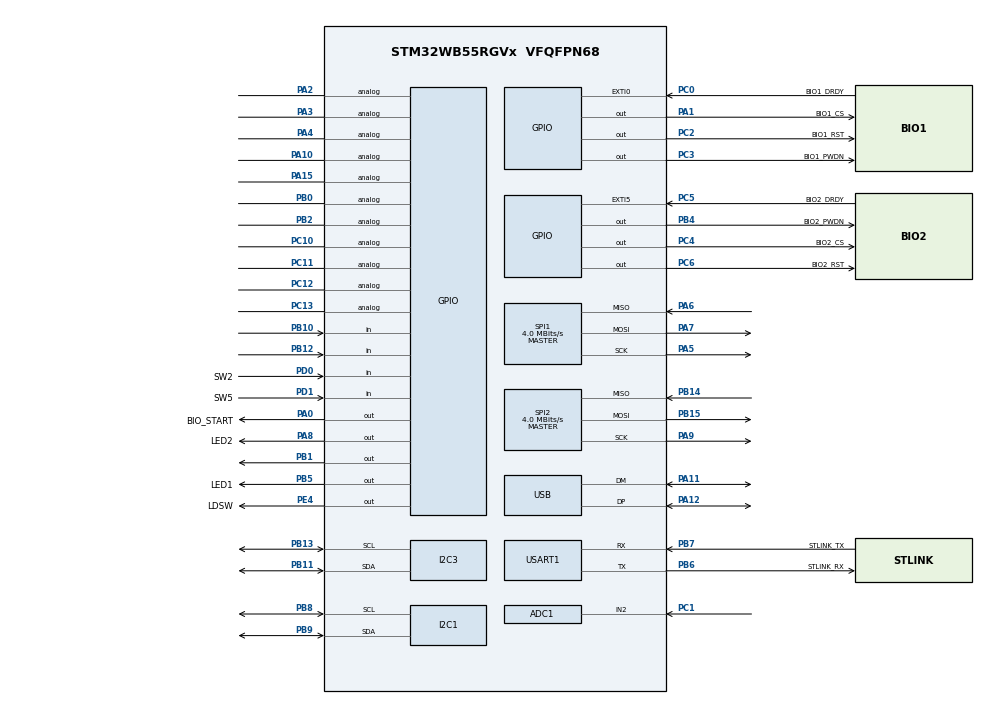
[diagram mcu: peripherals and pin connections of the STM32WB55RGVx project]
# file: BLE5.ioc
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ADC1.Channel-0\#ChannelRegularConversion=ADC_CHANNEL_2
ADC1.NbrOfConversionFlag=1
ADC1.OffsetNumber-0\#ChannelRegularConversion=ADC_OFFSET_NONE
ADC1.Rank-0\#ChannelRegularConversion=1
ADC1.SamplingTime-0\#ChannelRegularConversion=ADC_SAMPLETIME_2CYCLES_5
ADC1.master=1
AES1.KeySize=CRYP_KEYSIZE_256B
Dma.Request0=USART1_TX
Dma.Request1=SPI1_RX
Dma.Request2=SPI1_TX
Dma.SPI1_RX.1.Direction=DMA_PERIPH_TO_MEMORY
Dma.SPI1_RX.1.EventEnable=DISABLE
Dma.SPI1_RX.1.Instance=DMA1_Channel2
Dma.SPI1_RX.1.MemDataAlignment=DMA_MDATAALIGN_BYTE
Dma.SPI1_RX.1.MemInc=DMA_MINC_ENABLE
Dma.SPI1_RX.1.Mode=DMA_NORMAL
Dma.SPI1_RX.1.PeriphDataAlignment=DMA_PDATAALIGN_BYTE
Dma.SPI1_RX.1.PeriphInc=DMA_PINC_DISABLE
Dma.SPI1_RX.1.Polarity=HAL_DMAMUX_REQ_GEN_RISING
Dma.SPI1_RX.1.Priority=DMA_PRIORITY_LOW
Dma.SPI1_RX.1.RequestNumber=1
Dma.SPI1_RX.1.SignalID=NONE
Dma.SPI1_RX.1.SyncEnable=DISABLE
Dma.SPI1_RX.1.SyncPolarity=HAL_DMAMUX_SYNC_NO_EVENT
Dma.SPI1_RX.1.SyncRequestNumber=1
Dma.SPI1_RX.1.SyncSignalID=NONE
Dma.SPI1_TX.2.Direction=DMA_MEMORY_TO_PERIPH
Dma.SPI1_TX.2.EventEnable=DISABLE
Dma.SPI1_TX.2.Instance=DMA1_Channel3
Dma.SPI1_TX.2.MemDataAlignment=DMA_MDATAALIGN_BYTE
Dma.SPI1_TX.2.MemInc=DMA_MINC_ENABLE
Dma.SPI1_TX.2.Mode=DMA_NORMAL
Dma.SPI1_TX.2.PeriphDataAlignment=DMA_PDATAALIGN_BYTE
Dma.SPI1_TX.2.PeriphInc=DMA_PINC_DISABLE
Dma.SPI1_TX.2.Polarity=HAL_DMAMUX_REQ_GEN_RISING
Dma.SPI1_TX.2.Priority=DMA_PRIORITY_LOW
Dma.SPI1_TX.2.RequestNumber=1
Dma.SPI1_TX.2.SignalID=NONE
Dma.SPI1_TX.2.SyncEnable=DISABLE
Dma.SPI1_TX.2.SyncPolarity=HAL_DMAMUX_SYNC_NO_EVENT
Dma.SPI1_TX.2.SyncRequestNumber=1
Dma.SPI1_TX.2.SyncSignalID=NONE
Dma.USART1_TX.0.Direction=DMA_MEMORY_TO_PERIPH
Dma.USART1_TX.0.EventEnable=DISABLE
Dma.USART1_TX.0.Instance=DMA1_Channel1
Dma.USART1_TX.0.MemDataAlignment=DMA_MDATAALIGN_BYTE
Dma.USART1_TX.0.MemInc=DMA_MINC_ENABLE
Dma.USART1_TX.0.Mode=DMA_NORMAL
Dma.USART1_TX.0.PeriphDataAlignment=DMA_PDATAALIGN_BYTE
Dma.USART1_TX.0.PeriphInc=DMA_PINC_DISABLE
Dma.USART1_TX.0.Polarity=HAL_DMAMUX_REQ_GEN_RISING
Dma.USART1_TX.0.Priority=DMA_PRIORITY_LOW
Dma.USART1_TX.0.RequestNumber=1
Dma.USART1_TX.0.SignalID=NONE
Dma.USART1_TX.0.SyncEnable=DISABLE
Dma.USART1_TX.0.SyncPolarity=HAL_DMAMUX_SYNC_NO_EVENT
Dma.USART1_TX.0.SyncRequestNumber=1
Dma.USART1_TX.0.SyncSignalID=NONE
I2C1.Timing=0x10707DBC
I2C3.Timing=0x10707DBC
Mcu.Family=STM32WB
Mcu.Name=STM32WB55RGVx
Mcu.Package=VFQFPN68
NVIC.DMA1_Channel1_IRQn=true\:0\:0\:false\:false\:true\:false\:true
NVIC.DMA1_Channel2_IRQn=true\:0\:0\:false\:false\:true\:false\:true
NVIC.DMA1_Channel3_IRQn=true\:0\:0\:false\:false\:true\:false\:true
NVIC.PriorityGroup=NVIC_PRIORITYGROUP_4
NVIC.TIM1_UP_TIM16_IRQn=true\:0\:0\:false\:false\:true\:false\:true
NVIC.TimeBase=TIM1_UP_TIM16_IRQn
NVIC.TimeBaseIP=TIM16
NVIC.USB_LP_IRQn=true\:0\:0\:false\:false\:true\:false\:true
OSC_IN.Mode=HSE-External-Oscillator
OSC_IN.Signal=RCC_OSC_IN
OSC_OUT.Mode=HSE-External-Oscillator
OSC_OUT.Signal=RCC_OSC_OUT
PA0.GPIO_Label=BIO_START
PA0.Signal=GPIO_Output
PA1.GPIO_Label=BIO1_CS
PA1.Signal=GPIO_Output
PA10.Signal=GPIO_Analog
PA11.Mode=Device
PA11.Signal=USB_DM
PA12.Mode=Device
PA12.Signal=USB_DP
PA13.GPIO_Label=JTMS
PA13.Mode=Trace_Asynchronous_SW
PA13.Signal=SYS_JTMS-SWDIO
PA14.GPIO_Label=JTCK
PA14.Mode=Trace_Asynchronous_SW
PA14.Signal=SYS_JTCK-SWCLK
PA15.Signal=GPIO_Analog
PA2.Signal=GPIO_Analog
PA3.Signal=GPIO_Analog
PA4.Signal=GPIO_Analog
PA5.Mode=Full_Duplex_Master
PA5.Signal=SPI1_SCK
PA6.Mode=Full_Duplex_Master
PA6.Signal=SPI1_MISO
PA7.Mode=Full_Duplex_Master
PA7.Signal=SPI1_MOSI
PA8.GPIO_Label=LED2
PA8.Signal=GPIO_Output
PA9.Mode=Full_Duplex_Master
PA9.Signal=SPI2_SCK
PB0.Signal=GPIO_Analog
PB1.Signal=GPIO_Output
PB10.Signal=GPIO_Input
PB11.Mode=I2C
PB11.Signal=I2C3_SDA
PB12.Signal=GPIO_Input
PB13.Mode=I2C
PB13.Signal=I2C3_SCL
PB14.Mode=Full_Duplex_Master
PB14.Signal=SPI2_MISO
PB15.Mode=Full_Duplex_Master
PB15.Signal=SPI2_MOSI
PB2.Signal=GPIO_Analog
PB3.GPIO_Label=JTDO
PB3.Mode=Trace_Asynchronous_SW
PB3.Signal=SYS_JTDO-SWO
PB4.GPIO_Label=BIO2_PWDN
PB4.Signal=GPIO_Output
PB5.GPIO_Label=LED1
PB5.Signal=GPIO_Output
PB6.GPIO_Label=STLINK_RX
PB6.Mode=Asynchronous
PB6.Signal=USART1_TX
PB7.GPIO_Label=STLINK_TX
PB7.Mode=Asynchronous
PB7.Signal=USART1_RX
PB8.Mode=I2C
PB8.Signal=I2C1_SCL
PB9.Mode=I2C
PB9.Signal=I2C1_SDA
PC0.GPIO_Label=BIO1_DRDY
PC0.GPIO_ModeDefaultEXTI=GPIO_MODE_IT_FALLING
PC0.Signal=GPXTI0
PC1.Signal=ADCx_IN2
PC10.Signal=GPIO_Analog
PC11.Signal=GPIO_Analog
PC12.Signal=GPIO_Analog
PC13.Signal=GPIO_Analog
PC14-OSC32_IN.Mode=LSE-External-Oscillator
PC14-OSC32_IN.Signal=RCC_OSC32_IN
PC15-OSC32_OUT.Mode=LSE-External-Oscillator
PC15-OSC32_OUT.Signal=RCC_OSC32_OUT
PC2.GPIO_Label=BIO1_RST
PC2.Signal=GPIO_Output
PC3.GPIO_Label=BIO1_PWDN
PC3.Signal=GPIO_Output
PC4.GPIO_Label=BIO2_CS
PC4.Signal=GPIO_Output
PC5.GPIO_Label=BIO2_DRDY
PC5.Signal=GPXTI5
PC6.GPIO_Label=BIO2_RST
PC6.Signal=GPIO_Output
PD0.GPIO_Label=SW2
PD0.Signal=GPIO_Input
PD1.GPIO_Label=SW5
PD1.Signal=GPIO_Input
PE4.GPIO_Label=LDSW
PE4.Signal=GPIO_Output
ProjectManager.HeapSize=0xE60
ProjectManager.StackSize=0x800
ProjectManager.TargetToolchain=EWARM V8
RCC.ADCFreq_Value=48000000
RCC.AHB2CLKDivider=RCC_SYSCLK_DIV2
RCC.AHBFreq_Value=64000000
RCC.APB1Freq_Value=64000000
RCC.APB1TimFreq_Value=64000000
RCC.APB2Freq_Value=64000000
RCC.APB2TimFreq_Value=64000000
RCC.APB3Freq_Value=16000000
RCC.CortexFreq_Value=64000000
RCC.HCLKFreq_Value=64000000
RCC.HSE_VALUE=32000000
RCC.HSI48_VALUE=48000000
RCC.HSI_VALUE=16000000
RCC.PLLN=32
RCC.PLLSAI1N=24
RCC.SMPSCLockSelectionVirtual=RCC_SMPSCLKSOURCE_HSE
RCC.SYSCLKFreq_VALUE=64000000
RCC.SYSCLKSource=RCC_SYSCLKSOURCE_PLLCLK
RCC.USBFreq_Value=48000000
RCC.VCOOutputFreq_Value=128000000
RF1.Mode=RF1_Activate
RF1.Signal=RF_RF1
SH.ADCx_IN2.0=ADC1_IN2,IN2-Single-Ended
SPI1.BaudRatePrescaler=SPI_BAUDRATEPRESCALER_16
SPI1.CalculateBaudRate=4.0 MBits/s
SPI1.DataSize=SPI_DATASIZE_8BIT
SPI1.Direction=SPI_DIRECTION_2LINES
SPI1.Mode=SPI_MODE_MASTER
SPI1.VirtualType=VM_MASTER
SPI2.BaudRatePrescaler=SPI_BAUDRATEPRESCALER_16
SPI2.CalculateBaudRate=4.0 MBits/s
SPI2.DataSize=SPI_DATASIZE_8BIT
SPI2.Direction=SPI_DIRECTION_2LINES
SPI2.Mode=SPI_MODE_MASTER
SPI2.VirtualType=VM_MASTER
STM32_WPAN.BLE_DBG_APP_EN=1
STM32_WPAN.BLE_DBG_P2P_STM_EN=1
STM32_WPAN.CFG_FAST_CONN_ADV_INTERVAL_MAX_HEXA=0xa0
STM32_WPAN.CFG_LP_CONN_ADV_INTERVAL_MAX_HEXA=0xfa0
USART1.VirtualMode-Asynchronous=VM_ASYNC
USART1.WordLength=WORDLENGTH_8B
USB_DEVICE.CLASS_NAME_FS=CDC
USB_DEVICE.VirtualMode=Cdc
USB_DEVICE.VirtualModeFS=Cdc_FS
VP_AES1_VS_AES.Mode=AES_Activate
VP_CRC_VS_CRC.Mode=CRC_Activate
VP_HSEM_VS_HSEM.Mode=HSEM_Activate
VP_IWDG_VS_IWDG.Mode=IWDG_Activate
VP_RTC_VS_RTC_Activate.Mode=RTC_Enabled
VP_RTC_VS_RTC_WakeUp_intern.Mode=WakeUp
VP_SEQUENCER_VS_SEQUENCER.Mode=SEQUENCER_Enabled
VP_STM32_WPAN_VS_BLE_HOST.Mode=STM32_WPAN_Enabled
VP_SYS_VS_tim16.Mode=TIM16
VP_TIM1_VS_ClockSourceITR.Mode=TriggerSource_ITR0
VP_TIM1_VS_ControllerModeReset.Mode=Reset Mode
VP_TIM2_VS_ClockSourceITR.Mode=TriggerSource_ITR1
VP_TIM2_VS_ControllerModeReset.Mode=Reset Mode
VP_TINY_LPM_VS_TINY_LPM.Mode=TINY_LPM_Enabled
VP_USB_DEVICE_VS_USB_DEVICE_CDC_FS.Mode=CDC_FS
board=P-NUCLEO-WB55-Nucleo

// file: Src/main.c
/* USER CODE BEGIN Header */
/**
  ******************************************************************************
  * @file           : main.c
  * @brief          : Main program body
  ******************************************************************************
  * @attention
  *
  * <h2><center>&copy; Copyright (c) 2020 STMicroelectronics.
  * All rights reserved.</center></h2>
  *
  * This software component is licensed by ST under Ultimate Liberty license
  * SLA0044, the "License"; You may not use this file except in compliance with
  * the License. You may obtain a copy of the License at:
  *                             www.st.com/SLA0044
  *
  ******************************************************************************
  */
/* USER CODE END Header */

#include "main.h"
#include "app_entry.h"
#include "app_common.h"
#include "usb_device.h"
#include "stm32_lpm.h"
#include "stm32_seq.h"
#include "dbg_trace.h"
#include "stm32wbxx_ll_rtc.h"

ADC_HandleTypeDef hadc1;

CRYP_HandleTypeDef hcryp1;
__ALIGN_BEGIN static const uint32_t pKeyAES1[8] __ALIGN_END = {
                            0x00000000,0x00000000,0x00000000,0x00000000,0x00000000,0x00000000,0x00000000,0x00000000};

CRC_HandleTypeDef hcrc;

I2C_HandleTypeDef hi2c1;
I2C_HandleTypeDef hi2c3;

IWDG_HandleTypeDef hiwdg;

RTC_HandleTypeDef hrtc;

SPI_HandleTypeDef hspi1;
SPI_HandleTypeDef hspi2;
DMA_HandleTypeDef hdma_spi1_rx;
DMA_HandleTypeDef hdma_spi1_tx;

TIM_HandleTypeDef htim1;
TIM_HandleTypeDef htim2;

UART_HandleTypeDef huart1;
DMA_HandleTypeDef hdma_usart1_tx;

void SystemClock_Config(void);
static void MX_GPIO_Init(void);
static void MX_DMA_Init(void);
static void MX_ADC1_Init(void);
static void MX_I2C1_Init(void);
static void MX_I2C3_Init(void);
static void MX_RTC_Init(void);
static void MX_SPI1_Init(void);
static void MX_SPI2_Init(void);
static void MX_TIM1_Init(void);
static void MX_TIM2_Init(void);
static void MX_USART1_UART_Init(void);
static void MX_CRC_Init(void);
static void MX_RF_Init(void);
static void MX_AES1_Init(void);
static void MX_IWDG_Init(void);
/* USER CODE BEGIN PFP */
static void Reset_BackupDomain( void );
static void Reset_Device( void );
static void Reset_IPCC( void );
static void Init_Exti( void );
/* USER CODE END PFP */

int main(void)
{

  /* MCU Configuration--------------------------------------------------------*/

  /* Reset of all peripherals, Initializes the Flash interface and the Systick. */
  HAL_Init();

  /* USER CODE BEGIN Init */
  Reset_Device();
  /* USER CODE END Init */

  /* Configure the system clock */
  SystemClock_Config();

  /* USER CODE BEGIN SysInit */

 Init_Exti( );
 MX_RTC_Init();
  /* USER CODE END SysInit */

  /* Initialize all configured peripherals */
  MX_GPIO_Init();
  MX_DMA_Init();
  MX_ADC1_Init();
  MX_I2C1_Init();
  MX_I2C3_Init();

  MX_SPI1_Init();
  MX_SPI2_Init();
  MX_TIM1_Init();
  MX_TIM2_Init();
  MX_USART1_UART_Init();
  MX_CRC_Init();
  MX_USB_Device_Init();
  MX_RF_Init();
  MX_AES1_Init();
 // MX_IWDG_Init(); // needs special settings to keep bluetooth connection stable!!!!!!

  /* Init code for STM32_WPAN */
  APPE_Init();

  /* Infinite loop */
  while (1)
  {

    /* USER CODE BEGIN 3 */
    UTIL_SEQ_Run( UTIL_SEQ_DEFAULT );
  }
  /* USER CODE END 3 */
}

void SystemClock_Config(void)
{
  RCC_OscInitTypeDef RCC_OscInitStruct = {0};
  RCC_ClkInitTypeDef RCC_ClkInitStruct = {0};
  RCC_PeriphCLKInitTypeDef PeriphClkInitStruct = {0};

  /** Configure LSE Drive Capability
  */
  __HAL_RCC_LSEDRIVE_CONFIG(LL_RCC_LSEDRIVE_LOW);
  /** Configure the main internal regulator output voltage
  */
  __HAL_PWR_VOLTAGESCALING_CONFIG(PWR_REGULATOR_VOLTAGE_SCALE1);
  /** Initializes the CPU, AHB and APB busses clocks
  */
  RCC_OscInitStruct.OscillatorType = RCC_OSCILLATORTYPE_HSI|RCC_OSCILLATORTYPE_LSI1
                              |RCC_OSCILLATORTYPE_HSE|RCC_OSCILLATORTYPE_LSE;
  RCC_OscInitStruct.HSEState = RCC_HSE_ON;
  RCC_OscInitStruct.LSEState = RCC_LSE_ON;
  RCC_OscInitStruct.HSIState = RCC_HSI_ON;
  RCC_OscInitStruct.HSICalibrationValue = RCC_HSICALIBRATION_DEFAULT;
  RCC_OscInitStruct.LSIState = RCC_LSI_ON;
  RCC_OscInitStruct.PLL.PLLState = RCC_PLL_ON;
  RCC_OscInitStruct.PLL.PLLSource = RCC_PLLSOURCE_HSE;
  RCC_OscInitStruct.PLL.PLLM = RCC_PLLM_DIV1;
  RCC_OscInitStruct.PLL.PLLN = 8;
  RCC_OscInitStruct.PLL.PLLP = RCC_PLLP_DIV2;
  RCC_OscInitStruct.PLL.PLLR = RCC_PLLR_DIV2;
  RCC_OscInitStruct.PLL.PLLQ = RCC_PLLQ_DIV2;
  if (HAL_RCC_OscConfig(&RCC_OscInitStruct) != HAL_OK)
  {
    Error_Handler();
  }
  /** Configure the SYSCLKSource, HCLK, PCLK1 and PCLK2 clocks dividers
  */
  RCC_ClkInitStruct.ClockType = RCC_CLOCKTYPE_HCLK4|RCC_CLOCKTYPE_HCLK2
                              |RCC_CLOCKTYPE_HCLK|RCC_CLOCKTYPE_SYSCLK
                              |RCC_CLOCKTYPE_PCLK1|RCC_CLOCKTYPE_PCLK2;
  RCC_ClkInitStruct.SYSCLKSource = RCC_SYSCLKSOURCE_PLLCLK;
  RCC_ClkInitStruct.AHBCLKDivider = RCC_SYSCLK_DIV1;
  RCC_ClkInitStruct.APB1CLKDivider = RCC_HCLK_DIV1;
  RCC_ClkInitStruct.APB2CLKDivider = RCC_HCLK_DIV1;
  RCC_ClkInitStruct.AHBCLK2Divider = RCC_SYSCLK_DIV2;
  RCC_ClkInitStruct.AHBCLK4Divider = RCC_SYSCLK_DIV1;

  if (HAL_RCC_ClockConfig(&RCC_ClkInitStruct, FLASH_LATENCY_3) != HAL_OK)
  {
    Error_Handler();
  }
  /** Enable the HSE Prescaler
  */
  __HAL_RCC_HSE_DIV2_ENABLE();
  /** Initializes the peripherals clocks
  */
  PeriphClkInitStruct.PeriphClockSelection = RCC_PERIPHCLK_SMPS|RCC_PERIPHCLK_RFWAKEUP
                              |RCC_PERIPHCLK_RTC|RCC_PERIPHCLK_USART1
                              |RCC_PERIPHCLK_I2C1|RCC_PERIPHCLK_I2C3
                              |RCC_PERIPHCLK_USB|RCC_PERIPHCLK_ADC;
  PeriphClkInitStruct.PLLSAI1.PLLN = 6;
  PeriphClkInitStruct.PLLSAI1.PLLP = RCC_PLLP_DIV2;
  PeriphClkInitStruct.PLLSAI1.PLLQ = RCC_PLLQ_DIV2;
  PeriphClkInitStruct.PLLSAI1.PLLR = RCC_PLLR_DIV2;
  PeriphClkInitStruct.PLLSAI1.PLLSAI1ClockOut = RCC_PLLSAI1_USBCLK|RCC_PLLSAI1_ADCCLK;
  PeriphClkInitStruct.Usart1ClockSelection = RCC_USART1CLKSOURCE_PCLK2;
  PeriphClkInitStruct.I2c1ClockSelection = RCC_I2C1CLKSOURCE_PCLK1;
  PeriphClkInitStruct.I2c3ClockSelection = RCC_I2C3CLKSOURCE_PCLK1;
  PeriphClkInitStruct.UsbClockSelection = RCC_USBCLKSOURCE_PLLSAI1;
  PeriphClkInitStruct.AdcClockSelection = RCC_ADCCLKSOURCE_PLLSAI1;
  PeriphClkInitStruct.RTCClockSelection = RCC_RTCCLKSOURCE_HSE_DIV32;
  PeriphClkInitStruct.RFWakeUpClockSelection = RCC_RFWKPCLKSOURCE_LSE;
  PeriphClkInitStruct.SmpsClockSelection = RCC_SMPSCLKSOURCE_HSE;
  PeriphClkInitStruct.SmpsDivSelection = RCC_SMPSCLKDIV_RANGE0;

  if (HAL_RCCEx_PeriphCLKConfig(&PeriphClkInitStruct) != HAL_OK)
  {
    Error_Handler();
  }

  HAL_PWR_EnableBkUpAccess(); /**< Enable access to the RTC registers */
  HAL_PWR_EnableBkUpAccess();

  /**
   * Select LSE clock
   */
  LL_RCC_LSE_Enable();
  while(!LL_RCC_LSE_IsReady());

  /**
   * Select wakeup source of BLE RF
   */
  LL_RCC_SetRFWKPClockSource(LL_RCC_RFWKP_CLKSOURCE_LSE);

}

static void MX_ADC1_Init(void)
{

  ADC_ChannelConfTypeDef sConfig = {0};

  /** Common config
  */
  hadc1.Instance = ADC1;
  hadc1.Init.ClockPrescaler = ADC_CLOCK_ASYNC_DIV1;
  hadc1.Init.Resolution = ADC_RESOLUTION_12B;
  hadc1.Init.DataAlign = ADC_DATAALIGN_RIGHT;
  hadc1.Init.ScanConvMode = ADC_SCAN_DISABLE;
  hadc1.Init.EOCSelection = ADC_EOC_SINGLE_CONV;
  hadc1.Init.LowPowerAutoWait = DISABLE;
  hadc1.Init.ContinuousConvMode = DISABLE;
  hadc1.Init.NbrOfConversion = 1;
  hadc1.Init.DiscontinuousConvMode = DISABLE;
  hadc1.Init.ExternalTrigConv = ADC_SOFTWARE_START;
  hadc1.Init.ExternalTrigConvEdge = ADC_EXTERNALTRIGCONVEDGE_NONE;
  hadc1.Init.DMAContinuousRequests = DISABLE;
  hadc1.Init.Overrun = ADC_OVR_DATA_PRESERVED;
  hadc1.Init.OversamplingMode = DISABLE;
  if (HAL_ADC_Init(&hadc1) != HAL_OK)
  {
    Error_Handler();
  }
  /** Configure Regular Channel
  */
  sConfig.Channel = ADC_CHANNEL_2;
  sConfig.Rank = ADC_REGULAR_RANK_1;
  sConfig.SamplingTime = ADC_SAMPLETIME_2CYCLES_5;
  sConfig.SingleDiff = ADC_SINGLE_ENDED;
  sConfig.OffsetNumber = ADC_OFFSET_NONE;
  sConfig.Offset = 0;
  if (HAL_ADC_ConfigChannel(&hadc1, &sConfig) != HAL_OK)
  {
    Error_Handler();
  }

}

static void MX_AES1_Init(void)
{

  hcryp1.Instance = AES1;
  hcryp1.Init.DataType = CRYP_DATATYPE_32B;
  hcryp1.Init.KeySize = CRYP_KEYSIZE_256B;
  hcryp1.Init.pKey = (uint32_t *)pKeyAES1;
  hcryp1.Init.Algorithm = CRYP_AES_ECB;
  hcryp1.Init.DataWidthUnit = CRYP_DATAWIDTHUNIT_WORD;
  hcryp1.Init.KeyIVConfigSkip = CRYP_KEYIVCONFIG_ALWAYS;
  if (HAL_CRYP_Init(&hcryp1) != HAL_OK)
  {
    Error_Handler();
  }

}

static void MX_CRC_Init(void)
{

  hcrc.Instance = CRC;
  hcrc.Init.DefaultPolynomialUse = DEFAULT_POLYNOMIAL_ENABLE;
  hcrc.Init.DefaultInitValueUse = DEFAULT_INIT_VALUE_ENABLE;
  hcrc.Init.InputDataInversionMode = CRC_INPUTDATA_INVERSION_NONE;
  hcrc.Init.OutputDataInversionMode = CRC_OUTPUTDATA_INVERSION_DISABLE;
  hcrc.InputDataFormat = CRC_INPUTDATA_FORMAT_BYTES;
  if (HAL_CRC_Init(&hcrc) != HAL_OK)
  {
    Error_Handler();
  }

}

static void MX_I2C1_Init(void)
{

  hi2c1.Instance = I2C1;
  hi2c1.Init.Timing = 0x10707DBC;
  hi2c1.Init.OwnAddress1 = 0;
  hi2c1.Init.AddressingMode = I2C_ADDRESSINGMODE_7BIT;
  hi2c1.Init.DualAddressMode = I2C_DUALADDRESS_DISABLE;
  hi2c1.Init.OwnAddress2 = 0;
  hi2c1.Init.OwnAddress2Masks = I2C_OA2_NOMASK;
  hi2c1.Init.GeneralCallMode = I2C_GENERALCALL_DISABLE;
  hi2c1.Init.NoStretchMode = I2C_NOSTRETCH_DISABLE;
  if (HAL_I2C_Init(&hi2c1) != HAL_OK)
  {
    Error_Handler();
  }
  /** Configure Analogue filter
  */
  if (HAL_I2CEx_ConfigAnalogFilter(&hi2c1, I2C_ANALOGFILTER_ENABLE) != HAL_OK)
  {
    Error_Handler();
  }
  /** Configure Digital filter
  */
  if (HAL_I2CEx_ConfigDigitalFilter(&hi2c1, 0) != HAL_OK)
  {
    Error_Handler();
  }

}

static void MX_I2C3_Init(void)
{

  hi2c3.Instance = I2C3;
  hi2c3.Init.Timing = 0x10707DBC;
  hi2c3.Init.OwnAddress1 = 0;
  hi2c3.Init.AddressingMode = I2C_ADDRESSINGMODE_7BIT;
  hi2c3.Init.DualAddressMode = I2C_DUALADDRESS_DISABLE;
  hi2c3.Init.OwnAddress2 = 0;
  hi2c3.Init.OwnAddress2Masks = I2C_OA2_NOMASK;
  hi2c3.Init.GeneralCallMode = I2C_GENERALCALL_DISABLE;
  hi2c3.Init.NoStretchMode = I2C_NOSTRETCH_DISABLE;
  if (HAL_I2C_Init(&hi2c3) != HAL_OK)
  {
    Error_Handler();
  }
  /** Configure Analogue filter
  */
  if (HAL_I2CEx_ConfigAnalogFilter(&hi2c3, I2C_ANALOGFILTER_ENABLE) != HAL_OK)
  {
    Error_Handler();
  }
  /** Configure Digital filter
  */
  if (HAL_I2CEx_ConfigDigitalFilter(&hi2c3, 0) != HAL_OK)
  {
    Error_Handler();
  }

}

static void MX_IWDG_Init(void)
{

  hiwdg.Instance = IWDG;
  hiwdg.Init.Prescaler = IWDG_PRESCALER_4;
  hiwdg.Init.Window = 4095;
  hiwdg.Init.Reload = 4095;
  if (HAL_IWDG_Init(&hiwdg) != HAL_OK)
  {
    Error_Handler();
  }

}

static void MX_RF_Init(void)
{

}

static void MX_RTC_Init(void)
{

  /** Initialize RTC Only
  */
   HAL_PWR_EnableBkUpAccess(); /**< Enable access to the RTC registers */

  /**
   *  Write twice the value to flush the APB-AHB bridge
   *  This bit shall be written in the register before writing the next one
   */
  HAL_PWR_EnableBkUpAccess();

   __HAL_RCC_RTC_ENABLE(); //**< Enable RTC */?????

  hrtc.Instance = RTC;
  hrtc.Init.HourFormat = RTC_HOURFORMAT_24;
  hrtc.Init.AsynchPrediv = CFG_RTC_ASYNCH_PRESCALER;
  hrtc.Init.SynchPrediv = CFG_RTC_SYNCH_PRESCALER ;
  hrtc.Init.OutPut = RTC_OUTPUT_DISABLE;
  hrtc.Init.OutPutPolarity = RTC_OUTPUT_POLARITY_HIGH;
  hrtc.Init.OutPutType = RTC_OUTPUT_TYPE_OPENDRAIN;
  if (HAL_RTC_Init(&hrtc) != HAL_OK)
  {
    Error_Handler();
  }
  /** Enable the WakeUp
  */

//  /* Disable RTC registers write protection */
 LL_RTC_DisableWriteProtection(RTC);
//
  LL_RTC_WAKEUP_SetClock(RTC, CFG_RTC_WUCKSEL_DIVIDER);

  /* Enable RTC registers write protection */
  LL_RTC_EnableWriteProtection(RTC);

  return;

}

static void MX_SPI1_Init(void)
{

  /* SPI1 parameter configuration*/
  hspi1.Instance = SPI1;
  hspi1.Init.Mode = SPI_MODE_MASTER;
  hspi1.Init.Direction = SPI_DIRECTION_2LINES;
  hspi1.Init.DataSize = SPI_DATASIZE_8BIT;
  hspi1.Init.CLKPolarity = SPI_POLARITY_LOW;
  hspi1.Init.CLKPhase = SPI_PHASE_1EDGE;
  hspi1.Init.NSS = SPI_NSS_SOFT;
  hspi1.Init.BaudRatePrescaler = SPI_BAUDRATEPRESCALER_16;
  hspi1.Init.FirstBit = SPI_FIRSTBIT_MSB;
  hspi1.Init.TIMode = SPI_TIMODE_DISABLE;
  hspi1.Init.CRCCalculation = SPI_CRCCALCULATION_DISABLE;
  hspi1.Init.CRCPolynomial = 7;
  hspi1.Init.CRCLength = SPI_CRC_LENGTH_DATASIZE;
  hspi1.Init.NSSPMode = SPI_NSS_PULSE_ENABLE;
  if (HAL_SPI_Init(&hspi1) != HAL_OK)
  {
    Error_Handler();
  }

}

static void MX_SPI2_Init(void)
{

  /* SPI2 parameter configuration*/
  hspi2.Instance = SPI2;
  hspi2.Init.Mode = SPI_MODE_MASTER;
  hspi2.Init.Direction = SPI_DIRECTION_2LINES;
  hspi2.Init.DataSize = SPI_DATASIZE_8BIT;
  hspi2.Init.CLKPolarity = SPI_POLARITY_LOW;
  hspi2.Init.CLKPhase = SPI_PHASE_1EDGE;
  hspi2.Init.NSS = SPI_NSS_SOFT;
  hspi2.Init.BaudRatePrescaler = SPI_BAUDRATEPRESCALER_16;
  hspi2.Init.FirstBit = SPI_FIRSTBIT_MSB;
  hspi2.Init.TIMode = SPI_TIMODE_DISABLE;
  hspi2.Init.CRCCalculation = SPI_CRCCALCULATION_DISABLE;
  hspi2.Init.CRCPolynomial = 7;
  hspi2.Init.CRCLength = SPI_CRC_LENGTH_DATASIZE;
  hspi2.Init.NSSPMode = SPI_NSS_PULSE_ENABLE;
  if (HAL_SPI_Init(&hspi2) != HAL_OK)
  {
    Error_Handler();
  }

}

static void MX_TIM1_Init(void)
{

  TIM_SlaveConfigTypeDef sSlaveConfig = {0};
  TIM_MasterConfigTypeDef sMasterConfig = {0};

  htim1.Instance = TIM1;
  htim1.Init.Prescaler = 0;
  htim1.Init.CounterMode = TIM_COUNTERMODE_UP;
  htim1.Init.Period = 0;
  htim1.Init.ClockDivision = TIM_CLOCKDIVISION_DIV1;
  htim1.Init.RepetitionCounter = 0;
  htim1.Init.AutoReloadPreload = TIM_AUTORELOAD_PRELOAD_DISABLE;
  if (HAL_TIM_Base_Init(&htim1) != HAL_OK)
  {
    Error_Handler();
  }
  sSlaveConfig.SlaveMode = TIM_SLAVEMODE_RESET;
  sSlaveConfig.InputTrigger = TIM_TS_ITR0;
  if (HAL_TIM_SlaveConfigSynchro(&htim1, &sSlaveConfig) != HAL_OK)
  {
    Error_Handler();
  }
  sMasterConfig.MasterOutputTrigger = TIM_TRGO_RESET;
  sMasterConfig.MasterOutputTrigger2 = TIM_TRGO2_RESET;
  sMasterConfig.MasterSlaveMode = TIM_MASTERSLAVEMODE_DISABLE;
  if (HAL_TIMEx_MasterConfigSynchronization(&htim1, &sMasterConfig) != HAL_OK)
  {
    Error_Handler();
  }

}

static void MX_TIM2_Init(void)
{

  TIM_SlaveConfigTypeDef sSlaveConfig = {0};
  TIM_MasterConfigTypeDef sMasterConfig = {0};

  htim2.Instance = TIM2;
  htim2.Init.Prescaler = 0;
  htim2.Init.CounterMode = TIM_COUNTERMODE_UP;
  htim2.Init.Period = 0;
  htim2.Init.ClockDivision = TIM_CLOCKDIVISION_DIV1;
  htim2.Init.AutoReloadPreload = TIM_AUTORELOAD_PRELOAD_DISABLE;
  if (HAL_TIM_Base_Init(&htim2) != HAL_OK)
  {
    Error_Handler();
  }
  sSlaveConfig.SlaveMode = TIM_SLAVEMODE_RESET;
  sSlaveConfig.InputTrigger = TIM_TS_ITR1;
  if (HAL_TIM_SlaveConfigSynchro(&htim2, &sSlaveConfig) != HAL_OK)
  {
    Error_Handler();
  }
  sMasterConfig.MasterOutputTrigger = TIM_TRGO_RESET;
  sMasterConfig.MasterSlaveMode = TIM_MASTERSLAVEMODE_DISABLE;
  if (HAL_TIMEx_MasterConfigSynchronization(&htim2, &sMasterConfig) != HAL_OK)
  {
    Error_Handler();
  }
  if (HAL_TIMEx_RemapConfig(&htim2, TIM_TIM2_ITR_USB) != HAL_OK)
  {
    Error_Handler();
  }

}

static void MX_USART1_UART_Init(void)
{

  huart1.Instance = USART1;
  huart1.Init.BaudRate = 115200;
  huart1.Init.WordLength = UART_WORDLENGTH_8B;
  huart1.Init.StopBits = UART_STOPBITS_1;
  huart1.Init.Parity = UART_PARITY_NONE;
  huart1.Init.Mode = UART_MODE_TX_RX;
  huart1.Init.HwFlowCtl = UART_HWCONTROL_NONE;
  huart1.Init.OverSampling = UART_OVERSAMPLING_16;
  huart1.Init.OneBitSampling = UART_ONE_BIT_SAMPLE_DISABLE;
  huart1.Init.ClockPrescaler = UART_PRESCALER_DIV1;
  huart1.AdvancedInit.AdvFeatureInit = UART_ADVFEATURE_NO_INIT;
  if (HAL_UART_Init(&huart1) != HAL_OK)
  {
    Error_Handler();
  }
  if (HAL_UARTEx_SetTxFifoThreshold(&huart1, UART_TXFIFO_THRESHOLD_1_8) != HAL_OK)
  {
    Error_Handler();
  }
  if (HAL_UARTEx_SetRxFifoThreshold(&huart1, UART_RXFIFO_THRESHOLD_1_8) != HAL_OK)
  {
    Error_Handler();
  }
  if (HAL_UARTEx_DisableFifoMode(&huart1) != HAL_OK)
  {
    Error_Handler();
  }

}

static void MX_DMA_Init(void)
{

  /* DMA controller clock enable */
  __HAL_RCC_DMAMUX1_CLK_ENABLE();
  __HAL_RCC_DMA1_CLK_ENABLE();

  /* DMA interrupt init */
  /* DMA1_Channel1_IRQn interrupt configuration */
  HAL_NVIC_SetPriority(DMA1_Channel1_IRQn, 0, 0);
  HAL_NVIC_EnableIRQ(DMA1_Channel1_IRQn);
  /* DMA1_Channel2_IRQn interrupt configuration */
  HAL_NVIC_SetPriority(DMA1_Channel2_IRQn, 0, 0);
  HAL_NVIC_EnableIRQ(DMA1_Channel2_IRQn);
  /* DMA1_Channel3_IRQn interrupt configuration */
  HAL_NVIC_SetPriority(DMA1_Channel3_IRQn, 0, 0);
  HAL_NVIC_EnableIRQ(DMA1_Channel3_IRQn);

}

static void MX_GPIO_Init(void)
{
  GPIO_InitTypeDef GPIO_InitStruct = {0};

  /* GPIO Ports Clock Enable */
  __HAL_RCC_GPIOC_CLK_ENABLE();
  __HAL_RCC_GPIOB_CLK_ENABLE();
  __HAL_RCC_GPIOA_CLK_ENABLE();
  __HAL_RCC_GPIOE_CLK_ENABLE();
  __HAL_RCC_GPIOD_CLK_ENABLE();

  /*Configure GPIO pin Output Level */
  HAL_GPIO_WritePin(GPIOC, BIO1_RST_Pin|BIO1_PWDN_Pin|BIO2_CS_Pin|BIO2_RST_Pin, GPIO_PIN_RESET);

  /*Configure GPIO pin Output Level */
  HAL_GPIO_WritePin(GPIOA, BIO_START_Pin|BIO1_CS_Pin|LED2_Pin, GPIO_PIN_RESET);

  /*Configure GPIO pin Output Level */
  HAL_GPIO_WritePin(GPIOB, GPIO_PIN_1|BIO2_PWDN_Pin|LED1_Pin, GPIO_PIN_RESET);

  /*Configure GPIO pin Output Level */
  HAL_GPIO_WritePin(LDSW_GPIO_Port, LDSW_Pin, GPIO_PIN_RESET);

  /*Configure GPIO pins : PC13 PC10 PC11 PC12 */
  GPIO_InitStruct.Pin = GPIO_PIN_13|GPIO_PIN_10|GPIO_PIN_11|GPIO_PIN_12;
  GPIO_InitStruct.Mode = GPIO_MODE_ANALOG;
  GPIO_InitStruct.Pull = GPIO_NOPULL;
  HAL_GPIO_Init(GPIOC, &GPIO_InitStruct);

  /*Configure GPIO pin : BIO1_DRDY_Pin */
  GPIO_InitStruct.Pin = BIO1_DRDY_Pin;
  GPIO_InitStruct.Mode = GPIO_MODE_IT_FALLING;
  GPIO_InitStruct.Pull = GPIO_NOPULL;
  HAL_GPIO_Init(BIO1_DRDY_GPIO_Port, &GPIO_InitStruct);

  /*Configure GPIO pins : BIO1_RST_Pin BIO1_PWDN_Pin BIO2_CS_Pin BIO2_RST_Pin */
  GPIO_InitStruct.Pin = BIO1_RST_Pin|BIO1_PWDN_Pin|BIO2_CS_Pin|BIO2_RST_Pin;
  GPIO_InitStruct.Mode = GPIO_MODE_OUTPUT_PP;
  GPIO_InitStruct.Pull = GPIO_NOPULL;
  GPIO_InitStruct.Speed = GPIO_SPEED_FREQ_LOW;
  HAL_GPIO_Init(GPIOC, &GPIO_InitStruct);

  /*Configure GPIO pins : BIO_START_Pin BIO1_CS_Pin LED2_Pin */
  GPIO_InitStruct.Pin = BIO_START_Pin|BIO1_CS_Pin|LED2_Pin;
  GPIO_InitStruct.Mode = GPIO_MODE_OUTPUT_PP;
  GPIO_InitStruct.Pull = GPIO_NOPULL;
  GPIO_InitStruct.Speed = GPIO_SPEED_FREQ_LOW;
  HAL_GPIO_Init(GPIOA, &GPIO_InitStruct);

  /*Configure GPIO pins : PA2 PA3 PA4 PA10
                           PA15 */
  GPIO_InitStruct.Pin = GPIO_PIN_2|GPIO_PIN_3|GPIO_PIN_4|GPIO_PIN_10
                          |GPIO_PIN_15;
  GPIO_InitStruct.Mode = GPIO_MODE_ANALOG;
  GPIO_InitStruct.Pull = GPIO_NOPULL;
  HAL_GPIO_Init(GPIOA, &GPIO_InitStruct);

  /*Configure GPIO pin : BIO2_DRDY_Pin */
  GPIO_InitStruct.Pin = BIO2_DRDY_Pin;
  GPIO_InitStruct.Mode = GPIO_MODE_IT_RISING;
  GPIO_InitStruct.Pull = GPIO_NOPULL;
  HAL_GPIO_Init(BIO2_DRDY_GPIO_Port, &GPIO_InitStruct);

  /*Configure GPIO pins : PB2 PB0 */
  GPIO_InitStruct.Pin = GPIO_PIN_2|GPIO_PIN_0;
  GPIO_InitStruct.Mode = GPIO_MODE_ANALOG;
  GPIO_InitStruct.Pull = GPIO_NOPULL;
  HAL_GPIO_Init(GPIOB, &GPIO_InitStruct);

  /*Configure GPIO pins : PB10 PB12 */
  GPIO_InitStruct.Pin = GPIO_PIN_10|GPIO_PIN_12;
  GPIO_InitStruct.Mode = GPIO_MODE_INPUT;
  GPIO_InitStruct.Pull = GPIO_NOPULL;
  HAL_GPIO_Init(GPIOB, &GPIO_InitStruct);

  /*Configure GPIO pins : PB1 BIO2_PWDN_Pin LED1_Pin */
  GPIO_InitStruct.Pin = GPIO_PIN_1|BIO2_PWDN_Pin|LED1_Pin;
  GPIO_InitStruct.Mode = GPIO_MODE_OUTPUT_PP;
  GPIO_InitStruct.Pull = GPIO_NOPULL;
  GPIO_InitStruct.Speed = GPIO_SPEED_FREQ_LOW;
  HAL_GPIO_Init(GPIOB, &GPIO_InitStruct);

  /*Configure GPIO pin : LDSW_Pin */
  GPIO_InitStruct.Pin = LDSW_Pin;
  GPIO_InitStruct.Mode = GPIO_MODE_OUTPUT_PP;
  GPIO_InitStruct.Pull = GPIO_NOPULL;
  GPIO_InitStruct.Speed = GPIO_SPEED_FREQ_LOW;
  HAL_GPIO_Init(LDSW_GPIO_Port, &GPIO_InitStruct);

  /*Configure GPIO pins : SW2_Pin SW5_Pin */
  GPIO_InitStruct.Pin = SW2_Pin|SW5_Pin;
  GPIO_InitStruct.Mode = GPIO_MODE_INPUT;
  GPIO_InitStruct.Pull = GPIO_NOPULL;
  HAL_GPIO_Init(GPIOD, &GPIO_InitStruct);

}

/* USER CODE BEGIN 4 */
static void Init_Exti( void )
{
  /**< Disable all wakeup interrupt on CPU1  except IPCC(36), HSEM(38) */
  LL_EXTI_DisableIT_0_31(~0);
  LL_EXTI_DisableIT_32_63( (~0) & (~(LL_EXTI_LINE_36 | LL_EXTI_LINE_38)) );

  return;
}

static void Reset_Device( void )
{
#if ( CFG_HW_RESET_BY_FW == 1 )
  Reset_BackupDomain();

  Reset_IPCC();
#endif

  return;
}

static void Reset_IPCC( void )
{
  LL_AHB3_GRP1_EnableClock(LL_AHB3_GRP1_PERIPH_IPCC);

  LL_C1_IPCC_ClearFlag_CHx(
      IPCC,
      LL_IPCC_CHANNEL_1 | LL_IPCC_CHANNEL_2 | LL_IPCC_CHANNEL_3 | LL_IPCC_CHANNEL_4
      | LL_IPCC_CHANNEL_5 | LL_IPCC_CHANNEL_6);

  LL_C2_IPCC_ClearFlag_CHx(
      IPCC,
      LL_IPCC_CHANNEL_1 | LL_IPCC_CHANNEL_2 | LL_IPCC_CHANNEL_3 | LL_IPCC_CHANNEL_4
      | LL_IPCC_CHANNEL_5 | LL_IPCC_CHANNEL_6);

  LL_C1_IPCC_DisableTransmitChannel(
      IPCC,
      LL_IPCC_CHANNEL_1 | LL_IPCC_CHANNEL_2 | LL_IPCC_CHANNEL_3 | LL_IPCC_CHANNEL_4
      | LL_IPCC_CHANNEL_5 | LL_IPCC_CHANNEL_6);

  LL_C2_IPCC_DisableTransmitChannel(
      IPCC,
      LL_IPCC_CHANNEL_1 | LL_IPCC_CHANNEL_2 | LL_IPCC_CHANNEL_3 | LL_IPCC_CHANNEL_4
      | LL_IPCC_CHANNEL_5 | LL_IPCC_CHANNEL_6);

  LL_C1_IPCC_DisableReceiveChannel(
      IPCC,
      LL_IPCC_CHANNEL_1 | LL_IPCC_CHANNEL_2 | LL_IPCC_CHANNEL_3 | LL_IPCC_CHANNEL_4
      | LL_IPCC_CHANNEL_5 | LL_IPCC_CHANNEL_6);

  LL_C2_IPCC_DisableReceiveChannel(
      IPCC,
      LL_IPCC_CHANNEL_1 | LL_IPCC_CHANNEL_2 | LL_IPCC_CHANNEL_3 | LL_IPCC_CHANNEL_4
      | LL_IPCC_CHANNEL_5 | LL_IPCC_CHANNEL_6);

  return;
}

static void Reset_BackupDomain( void )
{
  if ((LL_RCC_IsActiveFlag_PINRST() != FALSE) && (LL_RCC_IsActiveFlag_SFTRST() == FALSE))
  {
    HAL_PWR_EnableBkUpAccess(); /**< Enable access to the RTC registers */

    /**
     *  Write twice the value to flush the APB-AHB bridge
     *  This bit shall be written in the register before writing the next one
     */
    HAL_PWR_EnableBkUpAccess();

    __HAL_RCC_BACKUPRESET_FORCE();
    __HAL_RCC_BACKUPRESET_RELEASE();
  }

  return;
}

/* USER CODE END 4 */

void HAL_TIM_PeriodElapsedCallback(TIM_HandleTypeDef *htim)
{
  if (htim->Instance == TIM16) {
    HAL_IncTick();
  }
}

void Error_Handler(void)
{
}

/************************ (C) COPYRIGHT STMicroelectronics *****END OF FILE****/
